VERSION 5.8 ;
BUSBITCHARS "[]" ;
DIVIDERCHAR "/" ;
UNITS
    DATABASE MICRONS 1000 ;
END UNITS

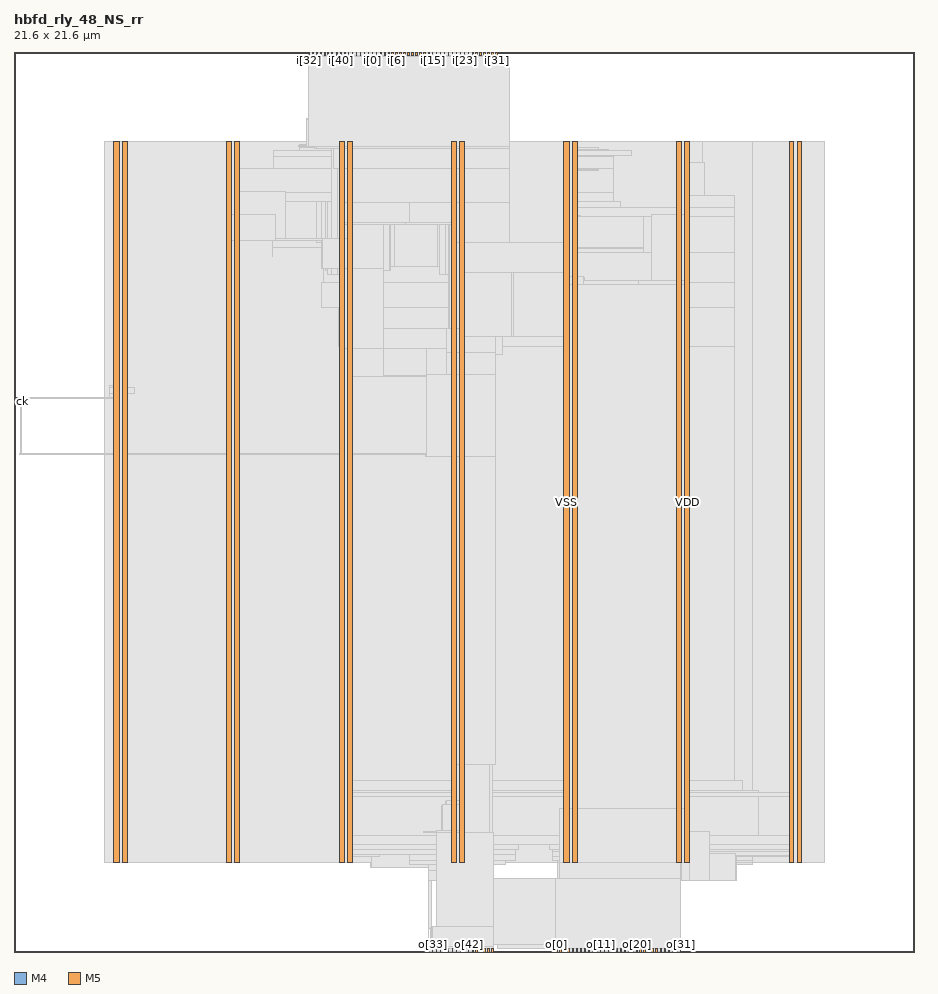
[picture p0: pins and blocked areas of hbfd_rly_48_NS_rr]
MACRO hbfd_rly_48_NS_rr
  FOREIGN hbfd_rly_48_NS_rr 0 0 ;
  CLASS BLOCK ;
  SIZE 21.6 BY 21.6 ;
  PIN ck
    DIRECTION INPUT ;
    USE SIGNAL ;
    PORT
      LAYER M4 ;
        RECT  0 13.2 0.084 13.224 ;
    END
  END ck
  PIN i[0]
    DIRECTION INPUT ;
    USE SIGNAL ;
    PORT
      LAYER M5 ;
        RECT  8.592 21.516 8.616 21.6 ;
    END
  END i[0]
  PIN i[10]
    DIRECTION INPUT ;
    USE SIGNAL ;
    PORT
      LAYER M5 ;
        RECT  9.552 21.516 9.576 21.6 ;
    END
  END i[10]
  PIN i[11]
    DIRECTION INPUT ;
    USE SIGNAL ;
    PORT
      LAYER M5 ;
        RECT  9.648 21.516 9.672 21.6 ;
    END
  END i[11]
  PIN i[12]
    DIRECTION INPUT ;
    USE SIGNAL ;
    PORT
      LAYER M5 ;
        RECT  9.744 21.516 9.768 21.6 ;
    END
  END i[12]
  PIN i[13]
    DIRECTION INPUT ;
    USE SIGNAL ;
    PORT
      LAYER M5 ;
        RECT  9.84 21.516 9.864 21.6 ;
    END
  END i[13]
  PIN i[14]
    DIRECTION INPUT ;
    USE SIGNAL ;
    PORT
      LAYER M5 ;
        RECT  9.936 21.516 9.96 21.6 ;
    END
  END i[14]
  PIN i[15]
    DIRECTION INPUT ;
    USE SIGNAL ;
    PORT
      LAYER M5 ;
        RECT  10.032 21.516 10.056 21.6 ;
    END
  END i[15]
  PIN i[16]
    DIRECTION INPUT ;
    USE SIGNAL ;
    PORT
      LAYER M5 ;
        RECT  10.128 21.516 10.152 21.6 ;
    END
  END i[16]
  PIN i[17]
    DIRECTION INPUT ;
    USE SIGNAL ;
    PORT
      LAYER M5 ;
        RECT  10.224 21.516 10.248 21.6 ;
    END
  END i[17]
  PIN i[18]
    DIRECTION INPUT ;
    USE SIGNAL ;
    PORT
      LAYER M5 ;
        RECT  10.32 21.516 10.344 21.6 ;
    END
  END i[18]
  PIN i[19]
    DIRECTION INPUT ;
    USE SIGNAL ;
    PORT
      LAYER M5 ;
        RECT  10.416 21.516 10.44 21.6 ;
    END
  END i[19]
  PIN i[1]
    DIRECTION INPUT ;
    USE SIGNAL ;
    PORT
      LAYER M5 ;
        RECT  8.688 21.516 8.712 21.6 ;
    END
  END i[1]
  PIN i[20]
    DIRECTION INPUT ;
    USE SIGNAL ;
    PORT
      LAYER M5 ;
        RECT  10.512 21.516 10.536 21.6 ;
    END
  END i[20]
  PIN i[21]
    DIRECTION INPUT ;
    USE SIGNAL ;
    PORT
      LAYER M5 ;
        RECT  10.608 21.516 10.632 21.6 ;
    END
  END i[21]
  PIN i[22]
    DIRECTION INPUT ;
    USE SIGNAL ;
    PORT
      LAYER M5 ;
        RECT  10.704 21.516 10.728 21.6 ;
    END
  END i[22]
  PIN i[23]
    DIRECTION INPUT ;
    USE SIGNAL ;
    PORT
      LAYER M5 ;
        RECT  10.8 21.516 10.824 21.6 ;
    END
  END i[23]
  PIN i[24]
    DIRECTION INPUT ;
    USE SIGNAL ;
    PORT
      LAYER M5 ;
        RECT  10.896 21.516 10.92 21.6 ;
    END
  END i[24]
  PIN i[25]
    DIRECTION INPUT ;
    USE SIGNAL ;
    PORT
      LAYER M5 ;
        RECT  10.992 21.516 11.016 21.6 ;
    END
  END i[25]
  PIN i[26]
    DIRECTION INPUT ;
    USE SIGNAL ;
    PORT
      LAYER M5 ;
        RECT  11.088 21.516 11.112 21.6 ;
    END
  END i[26]
  PIN i[27]
    DIRECTION INPUT ;
    USE SIGNAL ;
    PORT
      LAYER M5 ;
        RECT  11.184 21.516 11.208 21.6 ;
    END
  END i[27]
  PIN i[28]
    DIRECTION INPUT ;
    USE SIGNAL ;
    PORT
      LAYER M5 ;
        RECT  11.28 21.516 11.304 21.6 ;
    END
  END i[28]
  PIN i[29]
    DIRECTION INPUT ;
    USE SIGNAL ;
    PORT
      LAYER M5 ;
        RECT  11.376 21.516 11.4 21.6 ;
    END
  END i[29]
  PIN i[2]
    DIRECTION INPUT ;
    USE SIGNAL ;
    PORT
      LAYER M5 ;
        RECT  8.784 21.516 8.808 21.6 ;
    END
  END i[2]
  PIN i[30]
    DIRECTION INPUT ;
    USE SIGNAL ;
    PORT
      LAYER M5 ;
        RECT  11.472 21.516 11.496 21.6 ;
    END
  END i[30]
  PIN i[31]
    DIRECTION INPUT ;
    USE SIGNAL ;
    PORT
      LAYER M5 ;
        RECT  11.568 21.516 11.592 21.6 ;
    END
  END i[31]
  PIN i[32]
    DIRECTION INPUT ;
    USE SIGNAL ;
    PORT
      LAYER M5 ;
        RECT  7.056 21.516 7.08 21.6 ;
    END
  END i[32]
  PIN i[33]
    DIRECTION INPUT ;
    USE SIGNAL ;
    PORT
      LAYER M5 ;
        RECT  7.152 21.516 7.176 21.6 ;
    END
  END i[33]
  PIN i[34]
    DIRECTION INPUT ;
    USE SIGNAL ;
    PORT
      LAYER M5 ;
        RECT  7.248 21.516 7.272 21.6 ;
    END
  END i[34]
  PIN i[35]
    DIRECTION INPUT ;
    USE SIGNAL ;
    PORT
      LAYER M5 ;
        RECT  7.344 21.516 7.368 21.6 ;
    END
  END i[35]
  PIN i[36]
    DIRECTION INPUT ;
    USE SIGNAL ;
    PORT
      LAYER M5 ;
        RECT  7.44 21.516 7.464 21.6 ;
    END
  END i[36]
  PIN i[37]
    DIRECTION INPUT ;
    USE SIGNAL ;
    PORT
      LAYER M5 ;
        RECT  7.536 21.516 7.56 21.6 ;
    END
  END i[37]
  PIN i[38]
    DIRECTION INPUT ;
    USE SIGNAL ;
    PORT
      LAYER M5 ;
        RECT  7.632 21.516 7.656 21.6 ;
    END
  END i[38]
  PIN i[39]
    DIRECTION INPUT ;
    USE SIGNAL ;
    PORT
      LAYER M5 ;
        RECT  7.728 21.516 7.752 21.6 ;
    END
  END i[39]
  PIN i[3]
    DIRECTION INPUT ;
    USE SIGNAL ;
    PORT
      LAYER M5 ;
        RECT  8.88 21.516 8.904 21.6 ;
    END
  END i[3]
  PIN i[40]
    DIRECTION INPUT ;
    USE SIGNAL ;
    PORT
      LAYER M5 ;
        RECT  7.824 21.516 7.848 21.6 ;
    END
  END i[40]
  PIN i[41]
    DIRECTION INPUT ;
    USE SIGNAL ;
    PORT
      LAYER M5 ;
        RECT  7.92 21.516 7.944 21.6 ;
    END
  END i[41]
  PIN i[42]
    DIRECTION INPUT ;
    USE SIGNAL ;
    PORT
      LAYER M5 ;
        RECT  8.016 21.516 8.04 21.6 ;
    END
  END i[42]
  PIN i[43]
    DIRECTION INPUT ;
    USE SIGNAL ;
    PORT
      LAYER M5 ;
        RECT  8.112 21.516 8.136 21.6 ;
    END
  END i[43]
  PIN i[44]
    DIRECTION INPUT ;
    USE SIGNAL ;
    PORT
      LAYER M5 ;
        RECT  8.208 21.516 8.232 21.6 ;
    END
  END i[44]
  PIN i[45]
    DIRECTION INPUT ;
    USE SIGNAL ;
    PORT
      LAYER M5 ;
        RECT  8.304 21.516 8.328 21.6 ;
    END
  END i[45]
  PIN i[46]
    DIRECTION INPUT ;
    USE SIGNAL ;
    PORT
      LAYER M5 ;
        RECT  8.4 21.516 8.424 21.6 ;
    END
  END i[46]
  PIN i[47]
    DIRECTION INPUT ;
    USE SIGNAL ;
    PORT
      LAYER M5 ;
        RECT  8.496 21.516 8.52 21.6 ;
    END
  END i[47]
  PIN i[4]
    DIRECTION INPUT ;
    USE SIGNAL ;
    PORT
      LAYER M5 ;
        RECT  8.976 21.516 9 21.6 ;
    END
  END i[4]
  PIN i[5]
    DIRECTION INPUT ;
    USE SIGNAL ;
    PORT
      LAYER M5 ;
        RECT  9.072 21.516 9.096 21.6 ;
    END
  END i[5]
  PIN i[6]
    DIRECTION INPUT ;
    USE SIGNAL ;
    PORT
      LAYER M5 ;
        RECT  9.168 21.516 9.192 21.6 ;
    END
  END i[6]
  PIN i[7]
    DIRECTION INPUT ;
    USE SIGNAL ;
    PORT
      LAYER M5 ;
        RECT  9.264 21.516 9.288 21.6 ;
    END
  END i[7]
  PIN i[8]
    DIRECTION INPUT ;
    USE SIGNAL ;
    PORT
      LAYER M5 ;
        RECT  9.36 21.516 9.384 21.6 ;
    END
  END i[8]
  PIN i[9]
    DIRECTION INPUT ;
    USE SIGNAL ;
    PORT
      LAYER M5 ;
        RECT  9.456 21.516 9.48 21.6 ;
    END
  END i[9]
  PIN o[0]
    DIRECTION OUTPUT ;
    USE SIGNAL ;
    PORT
      LAYER M5 ;
        RECT  13.008 0 13.032 0.084 ;
    END
  END o[0]
  PIN o[10]
    DIRECTION OUTPUT ;
    USE SIGNAL ;
    PORT
      LAYER M5 ;
        RECT  13.968 0 13.992 0.084 ;
    END
  END o[10]
  PIN o[11]
    DIRECTION OUTPUT ;
    USE SIGNAL ;
    PORT
      LAYER M5 ;
        RECT  14.064 0 14.088 0.084 ;
    END
  END o[11]
  PIN o[12]
    DIRECTION OUTPUT ;
    USE SIGNAL ;
    PORT
      LAYER M5 ;
        RECT  14.16 0 14.184 0.084 ;
    END
  END o[12]
  PIN o[13]
    DIRECTION OUTPUT ;
    USE SIGNAL ;
    PORT
      LAYER M5 ;
        RECT  14.256 0 14.28 0.084 ;
    END
  END o[13]
  PIN o[14]
    DIRECTION OUTPUT ;
    USE SIGNAL ;
    PORT
      LAYER M5 ;
        RECT  14.352 0 14.376 0.084 ;
    END
  END o[14]
  PIN o[15]
    DIRECTION OUTPUT ;
    USE SIGNAL ;
    PORT
      LAYER M5 ;
        RECT  14.448 0 14.472 0.084 ;
    END
  END o[15]
  PIN o[16]
    DIRECTION OUTPUT ;
    USE SIGNAL ;
    PORT
      LAYER M5 ;
        RECT  14.544 0 14.568 0.084 ;
    END
  END o[16]
  PIN o[17]
    DIRECTION OUTPUT ;
    USE SIGNAL ;
    PORT
      LAYER M5 ;
        RECT  14.64 0 14.664 0.084 ;
    END
  END o[17]
  PIN o[18]
    DIRECTION OUTPUT ;
    USE SIGNAL ;
    PORT
      LAYER M5 ;
        RECT  14.736 0 14.76 0.084 ;
    END
  END o[18]
  PIN o[19]
    DIRECTION OUTPUT ;
    USE SIGNAL ;
    PORT
      LAYER M5 ;
        RECT  14.832 0 14.856 0.084 ;
    END
  END o[19]
  PIN o[1]
    DIRECTION OUTPUT ;
    USE SIGNAL ;
    PORT
      LAYER M5 ;
        RECT  13.104 0 13.128 0.084 ;
    END
  END o[1]
  PIN o[20]
    DIRECTION OUTPUT ;
    USE SIGNAL ;
    PORT
      LAYER M5 ;
        RECT  14.928 0 14.952 0.084 ;
    END
  END o[20]
  PIN o[21]
    DIRECTION OUTPUT ;
    USE SIGNAL ;
    PORT
      LAYER M5 ;
        RECT  15.024 0 15.048 0.084 ;
    END
  END o[21]
  PIN o[22]
    DIRECTION OUTPUT ;
    USE SIGNAL ;
    PORT
      LAYER M5 ;
        RECT  15.12 0 15.144 0.084 ;
    END
  END o[22]
  PIN o[23]
    DIRECTION OUTPUT ;
    USE SIGNAL ;
    PORT
      LAYER M5 ;
        RECT  15.216 0 15.24 0.084 ;
    END
  END o[23]
  PIN o[24]
    DIRECTION OUTPUT ;
    USE SIGNAL ;
    PORT
      LAYER M5 ;
        RECT  15.312 0 15.336 0.084 ;
    END
  END o[24]
  PIN o[25]
    DIRECTION OUTPUT ;
    USE SIGNAL ;
    PORT
      LAYER M5 ;
        RECT  15.408 0 15.432 0.084 ;
    END
  END o[25]
  PIN o[26]
    DIRECTION OUTPUT ;
    USE SIGNAL ;
    PORT
      LAYER M5 ;
        RECT  15.504 0 15.528 0.084 ;
    END
  END o[26]
  PIN o[27]
    DIRECTION OUTPUT ;
    USE SIGNAL ;
    PORT
      LAYER M5 ;
        RECT  15.6 0 15.624 0.084 ;
    END
  END o[27]
  PIN o[28]
    DIRECTION OUTPUT ;
    USE SIGNAL ;
    PORT
      LAYER M5 ;
        RECT  15.696 0 15.72 0.084 ;
    END
  END o[28]
  PIN o[29]
    DIRECTION OUTPUT ;
    USE SIGNAL ;
    PORT
      LAYER M5 ;
        RECT  15.792 0 15.816 0.084 ;
    END
  END o[29]
  PIN o[2]
    DIRECTION OUTPUT ;
    USE SIGNAL ;
    PORT
      LAYER M5 ;
        RECT  13.2 0 13.224 0.084 ;
    END
  END o[2]
  PIN o[30]
    DIRECTION OUTPUT ;
    USE SIGNAL ;
    PORT
      LAYER M5 ;
        RECT  15.888 0 15.912 0.084 ;
    END
  END o[30]
  PIN o[31]
    DIRECTION OUTPUT ;
    USE SIGNAL ;
    PORT
      LAYER M5 ;
        RECT  15.984 0 16.008 0.084 ;
    END
  END o[31]
  PIN o[32]
    DIRECTION OUTPUT ;
    USE SIGNAL ;
    PORT
      LAYER M5 ;
        RECT  9.936 0 9.96 0.084 ;
    END
  END o[32]
  PIN o[33]
    DIRECTION OUTPUT ;
    USE SIGNAL ;
    PORT
      LAYER M5 ;
        RECT  10.032 0 10.056 0.084 ;
    END
  END o[33]
  PIN o[34]
    DIRECTION OUTPUT ;
    USE SIGNAL ;
    PORT
      LAYER M5 ;
        RECT  10.128 0 10.152 0.084 ;
    END
  END o[34]
  PIN o[35]
    DIRECTION OUTPUT ;
    USE SIGNAL ;
    PORT
      LAYER M5 ;
        RECT  10.224 0 10.248 0.084 ;
    END
  END o[35]
  PIN o[36]
    DIRECTION OUTPUT ;
    USE SIGNAL ;
    PORT
      LAYER M5 ;
        RECT  10.32 0 10.344 0.084 ;
    END
  END o[36]
  PIN o[37]
    DIRECTION OUTPUT ;
    USE SIGNAL ;
    PORT
      LAYER M5 ;
        RECT  10.416 0 10.44 0.084 ;
    END
  END o[37]
  PIN o[38]
    DIRECTION OUTPUT ;
    USE SIGNAL ;
    PORT
      LAYER M5 ;
        RECT  10.512 0 10.536 0.084 ;
    END
  END o[38]
  PIN o[39]
    DIRECTION OUTPUT ;
    USE SIGNAL ;
    PORT
      LAYER M5 ;
        RECT  10.608 0 10.632 0.084 ;
    END
  END o[39]
  PIN o[3]
    DIRECTION OUTPUT ;
    USE SIGNAL ;
    PORT
      LAYER M5 ;
        RECT  13.296 0 13.32 0.084 ;
    END
  END o[3]
  PIN o[40]
    DIRECTION OUTPUT ;
    USE SIGNAL ;
    PORT
      LAYER M5 ;
        RECT  10.704 0 10.728 0.084 ;
    END
  END o[40]
  PIN o[41]
    DIRECTION OUTPUT ;
    USE SIGNAL ;
    PORT
      LAYER M5 ;
        RECT  10.8 0 10.824 0.084 ;
    END
  END o[41]
  PIN o[42]
    DIRECTION OUTPUT ;
    USE SIGNAL ;
    PORT
      LAYER M5 ;
        RECT  10.896 0 10.92 0.084 ;
    END
  END o[42]
  PIN o[43]
    DIRECTION OUTPUT ;
    USE SIGNAL ;
    PORT
      LAYER M5 ;
        RECT  10.992 0 11.016 0.084 ;
    END
  END o[43]
  PIN o[44]
    DIRECTION OUTPUT ;
    USE SIGNAL ;
    PORT
      LAYER M5 ;
        RECT  11.088 0 11.112 0.084 ;
    END
  END o[44]
  PIN o[45]
    DIRECTION OUTPUT ;
    USE SIGNAL ;
    PORT
      LAYER M5 ;
        RECT  11.184 0 11.208 0.084 ;
    END
  END o[45]
  PIN o[46]
    DIRECTION OUTPUT ;
    USE SIGNAL ;
    PORT
      LAYER M5 ;
        RECT  11.28 0 11.304 0.084 ;
    END
  END o[46]
  PIN o[47]
    DIRECTION OUTPUT ;
    USE SIGNAL ;
    PORT
      LAYER M5 ;
        RECT  11.376 0 11.4 0.084 ;
    END
  END o[47]
  PIN o[4]
    DIRECTION OUTPUT ;
    USE SIGNAL ;
    PORT
      LAYER M5 ;
        RECT  13.392 0 13.416 0.084 ;
    END
  END o[4]
  PIN o[5]
    DIRECTION OUTPUT ;
    USE SIGNAL ;
    PORT
      LAYER M5 ;
        RECT  13.488 0 13.512 0.084 ;
    END
  END o[5]
  PIN o[6]
    DIRECTION OUTPUT ;
    USE SIGNAL ;
    PORT
      LAYER M5 ;
        RECT  13.584 0 13.608 0.084 ;
    END
  END o[6]
  PIN o[7]
    DIRECTION OUTPUT ;
    USE SIGNAL ;
    PORT
      LAYER M5 ;
        RECT  13.68 0 13.704 0.084 ;
    END
  END o[7]
  PIN o[8]
    DIRECTION OUTPUT ;
    USE SIGNAL ;
    PORT
      LAYER M5 ;
        RECT  13.776 0 13.8 0.084 ;
    END
  END o[8]
  PIN o[9]
    DIRECTION OUTPUT ;
    USE SIGNAL ;
    PORT
      LAYER M5 ;
        RECT  13.872 0 13.896 0.084 ;
    END
  END o[9]
  PIN rs
    DIRECTION INPUT ;
    USE SIGNAL ;
    PORT
      LAYER M4 ;
        RECT  0 13.296 0.084 13.32 ;
    END
  END rs
  PIN rso
    DIRECTION OUTPUT ;
    USE SIGNAL ;
    PORT
      LAYER M5 ;
        RECT  11.472 0 11.496 0.084 ;
    END
  END rso
  PIN VDD
    DIRECTION INOUT ;
    USE POWER ;
    PORT
      LAYER M5 ;
        RECT  18.792 2.151 18.912 19.449 ;
        RECT  16.092 2.151 16.212 19.449 ;
        RECT  13.392 2.151 13.512 19.449 ;
        RECT  10.692 2.151 10.812 19.449 ;
        RECT  7.992 2.151 8.112 19.449 ;
        RECT  5.292 2.151 5.412 19.449 ;
        RECT  2.592 2.151 2.712 19.449 ;
    END
  END VDD
  PIN VSS
    DIRECTION INOUT ;
    USE GROUND ;
    PORT
      LAYER M5 ;
        RECT  18.6 2.137 18.72 19.463 ;
        RECT  15.9 2.137 16.02 19.463 ;
        RECT  13.2 2.137 13.32 19.463 ;
        RECT  10.5 2.137 10.62 19.463 ;
        RECT  7.8 2.137 7.92 19.463 ;
        RECT  5.1 2.137 5.22 19.463 ;
        RECT  2.4 2.137 2.52 19.463 ;
    END
  END VSS
  # OT_OBS_CLOSED layer=M5 d_um=1.536 added=14
  OBS
    LAYER RVTN ;
     RECT  2.16 2.16 19.44 2.295 ;
     RECT  2.16 2.565 19.44 2.835 ;
     RECT  2.16 3.105 19.44 3.375 ;
     RECT  2.16 3.645 19.44 3.915 ;
     RECT  2.16 4.185 19.44 4.455 ;
     RECT  2.16 4.725 19.44 4.995 ;
     RECT  2.16 5.265 19.44 5.535 ;
     RECT  2.16 5.805 19.44 6.075 ;
     RECT  2.16 6.345 19.44 6.615 ;
     RECT  2.16 6.885 19.44 7.155 ;
     RECT  2.16 7.425 19.44 7.695 ;
     RECT  2.16 7.965 19.44 8.235 ;
     RECT  2.16 8.505 19.44 8.775 ;
     RECT  2.16 9.045 19.44 9.315 ;
     RECT  2.16 9.585 19.44 9.855 ;
     RECT  2.16 10.125 19.44 10.395 ;
     RECT  2.16 10.665 19.44 10.935 ;
     RECT  2.16 11.205 19.44 11.475 ;
     RECT  2.16 11.745 19.44 12.015 ;
     RECT  2.16 12.285 19.44 12.555 ;
     RECT  2.16 12.825 19.44 13.095 ;
     RECT  2.16 13.365 19.44 13.635 ;
     RECT  2.16 13.905 19.44 14.175 ;
     RECT  2.16 14.445 19.44 14.715 ;
     RECT  2.16 14.985 19.44 15.255 ;
     RECT  2.16 15.525 19.44 15.795 ;
     RECT  2.16 16.065 19.44 16.335 ;
     RECT  2.16 16.605 19.44 16.875 ;
     RECT  2.16 17.145 19.44 17.415 ;
     RECT  2.16 17.685 19.44 17.955 ;
     RECT  2.16 18.225 19.44 18.495 ;
     RECT  2.16 18.765 19.44 19.035 ;
     RECT  2.16 19.305 19.44 19.44 ;
    LAYER RVTP ;
     RECT  2.16 2.295 19.44 2.565 ;
     RECT  2.16 2.835 19.44 3.105 ;
     RECT  2.16 3.375 19.44 3.645 ;
     RECT  2.16 3.915 19.44 4.185 ;
     RECT  2.16 4.455 19.44 4.725 ;
     RECT  2.16 4.995 19.44 5.265 ;
     RECT  2.16 5.535 19.44 5.805 ;
     RECT  2.16 6.075 19.44 6.345 ;
     RECT  2.16 6.615 19.44 6.885 ;
     RECT  2.16 7.155 19.44 7.425 ;
     RECT  2.16 7.695 19.44 7.965 ;
     RECT  2.16 8.235 19.44 8.505 ;
     RECT  2.16 8.775 19.44 9.045 ;
     RECT  2.16 9.315 19.44 9.585 ;
     RECT  2.16 9.855 19.44 10.125 ;
     RECT  2.16 10.395 19.44 10.665 ;
     RECT  2.16 10.935 19.44 11.205 ;
     RECT  2.16 11.475 19.44 11.745 ;
     RECT  2.16 12.015 19.44 12.285 ;
     RECT  2.16 12.555 19.44 12.825 ;
     RECT  2.16 13.095 19.44 13.365 ;
     RECT  2.16 13.635 19.44 13.905 ;
     RECT  2.16 14.175 19.44 14.445 ;
     RECT  2.16 14.715 19.44 14.985 ;
     RECT  2.16 15.255 19.44 15.525 ;
     RECT  2.16 15.795 19.44 16.065 ;
     RECT  2.16 16.335 19.44 16.605 ;
     RECT  2.16 16.875 19.44 17.145 ;
     RECT  2.16 17.415 19.44 17.685 ;
     RECT  2.16 17.955 19.44 18.225 ;
     RECT  2.16 18.495 19.44 18.765 ;
     RECT  2.16 19.035 19.44 19.305 ;
    LAYER M1 ;
     RECT  2.16 2.151 19.44 19.449 ;
    LAYER M2 ;
     RECT  2.16 2.151 8.563 19.449 ;
     RECT  8.563 2.034 10.355 19.449 ;
     RECT  10.355 2.07 11.363 19.449 ;
     RECT  11.363 2.106 11.795 19.449 ;
     RECT  14.251 1.152 14.495 1.17 ;
     RECT  11.795 2.151 16.519 19.449 ;
     RECT  16.519 2.106 17.735 19.449 ;
     RECT  17.735 2.151 19.44 19.449 ;
    LAYER M3 ;
     RECT  13.608 0.091 14.382 0.523 ;
     RECT  9.936 0.091 9.954 0.571 ;
     RECT  13.356 0.523 14.382 1.099 ;
     RECT  13.14 1.099 14.922 1.195 ;
     RECT  9.936 0.571 10.026 1.723 ;
     RECT  11.124 0.091 11.142 1.723 ;
     RECT  13.104 1.195 14.922 1.723 ;
     RECT  16.524 1.771 16.542 1.819 ;
     RECT  17.316 1.723 17.334 1.819 ;
     RECT  16.524 1.819 17.334 1.915 ;
     RECT  9.936 1.723 10.386 1.963 ;
     RECT  11.124 1.723 11.394 1.963 ;
     RECT  9.936 1.963 11.394 2.101 ;
     RECT  16.308 1.915 17.334 2.101 ;
     RECT  8.568 2.029 8.586 2.143 ;
     RECT  13.032 1.723 15.246 2.143 ;
     RECT  16.308 2.101 17.73 2.143 ;
     RECT  9.504 2.101 11.79 2.191 ;
     RECT  13.032 2.143 17.73 2.191 ;
     RECT  7.815 2.143 8.586 2.299 ;
     RECT  12.924 2.191 17.73 2.299 ;
     RECT  18.615 2.143 18.705 2.299 ;
     RECT  7.815 2.299 8.766 2.335 ;
     RECT  9.504 2.191 12.042 2.335 ;
     RECT  2.415 2.143 2.505 2.413 ;
     RECT  5.115 2.143 5.205 2.413 ;
     RECT  12.924 2.299 18.705 2.413 ;
     RECT  7.815 2.335 12.042 2.461 ;
     RECT  12.924 2.413 18.897 2.461 ;
     RECT  7.815 2.461 12.114 2.569 ;
     RECT  12.852 2.461 18.897 2.569 ;
     RECT  7.815 2.569 18.897 2.795 ;
     RECT  7.815 2.795 17.874 3.721 ;
     RECT  18.615 2.795 18.897 3.721 ;
     RECT  7.815 3.721 18.897 3.839 ;
     RECT  7.815 3.839 17.874 3.875 ;
     RECT  7.815 3.875 17.478 4.109 ;
     RECT  2.415 2.413 2.697 13.291 ;
     RECT  2.304 13.291 2.697 13.405 ;
     RECT  2.304 13.405 2.898 13.559 ;
     RECT  2.304 13.559 2.697 13.595 ;
     RECT  7.815 4.109 17.298 14.521 ;
     RECT  7.776 14.521 17.298 15.457 ;
     RECT  7.38 15.457 17.298 16.061 ;
     RECT  7.416 16.061 17.298 16.799 ;
     RECT  7.416 16.799 15.102 16.879 ;
     RECT  6.192 16.681 6.21 16.915 ;
     RECT  7.38 16.879 15.102 16.915 ;
     RECT  6.192 16.915 15.102 17.659 ;
     RECT  15.915 16.799 17.298 17.659 ;
     RECT  6.156 17.659 17.298 17.879 ;
     RECT  6.156 17.879 14.562 18.023 ;
     RECT  15.915 17.879 17.298 18.149 ;
     RECT  5.115 2.413 5.397 18.235 ;
     RECT  6.156 18.023 14.382 18.235 ;
     RECT  5.115 18.235 14.382 18.797 ;
     RECT  15.915 18.149 16.578 18.959 ;
     RECT  6.228 18.797 14.382 19.103 ;
     RECT  13.212 19.103 14.382 19.111 ;
     RECT  2.415 13.595 2.697 19.187 ;
     RECT  5.115 18.797 5.397 19.187 ;
     RECT  15.915 18.959 16.197 19.187 ;
     RECT  18.615 3.839 18.897 19.187 ;
     RECT  6.228 19.103 12.474 19.229 ;
     RECT  13.212 19.111 14.814 19.229 ;
     RECT  13.212 19.229 14.274 19.265 ;
     RECT  6.84 19.229 12.33 19.301 ;
     RECT  13.212 19.265 14.022 19.301 ;
     RECT  6.84 19.301 12.042 19.325 ;
     RECT  9.648 19.325 12.042 19.337 ;
     RECT  6.84 19.325 8.91 19.373 ;
     RECT  9.648 19.337 11.214 19.373 ;
     RECT  12.024 19.337 12.042 19.373 ;
     RECT  13.212 19.301 13.305 19.373 ;
     RECT  6.84 19.373 8.118 19.379 ;
     RECT  2.415 19.187 2.505 19.457 ;
     RECT  5.115 19.187 5.205 19.457 ;
     RECT  13.215 19.373 13.305 19.457 ;
     RECT  15.915 19.187 16.005 19.457 ;
     RECT  18.615 19.187 18.705 19.457 ;
     RECT  10.404 19.373 11.034 19.565 ;
     RECT  7.02 19.379 8.118 19.613 ;
     RECT  10.476 19.565 11.034 19.613 ;
     RECT  7.02 19.613 7.794 19.661 ;
     RECT  7.02 19.661 7.65 19.997 ;
     RECT  7.38 19.997 7.65 20.045 ;
     RECT  7.632 20.045 7.65 20.573 ;
     RECT  11.016 19.613 11.034 21.485 ;
    LAYER M4 ;
     RECT  0.084 13.2 0.179 13.224 ;
     RECT  0.06 13.224 0.179 13.296 ;
     RECT  0.084 13.296 0.179 13.32 ;
     RECT  0.133 11.952 2.408 11.976 ;
     RECT  0.179 13.296 2.408 13.32 ;
     RECT  2.408 2.148 2.512 19.452 ;
     RECT  2.512 2.418 2.704 19.182 ;
     RECT  2.704 11.952 5.108 11.976 ;
     RECT  5.108 2.148 5.212 19.452 ;
     RECT  5.212 2.418 5.404 19.182 ;
     RECT  5.404 17.088 6.509 18.264 ;
     RECT  6.829 19.344 7.009 19.368 ;
     RECT  7.009 19.344 7.217 19.992 ;
     RECT  6.509 17.088 7.261 18.024 ;
     RECT  7.261 17.04 7.369 18.024 ;
     RECT  7.217 19.296 7.369 19.992 ;
     RECT  7.369 16.896 7.381 18.024 ;
     RECT  7.381 16.416 7.477 18.024 ;
     RECT  7.477 16.368 7.513 18.024 ;
     RECT  7.369 19.296 7.621 20.04 ;
     RECT  7.513 16.272 7.628 18.024 ;
     RECT  7.621 19.296 7.628 20.568 ;
     RECT  7.628 16.272 7.763 20.568 ;
     RECT  5.404 11.952 7.808 11.976 ;
     RECT  7.763 16.272 7.808 19.656 ;
     RECT  7.808 2.148 7.912 19.656 ;
     RECT  7.912 2.418 7.955 19.656 ;
     RECT  7.955 2.418 8.104 19.608 ;
     RECT  8.104 16.272 8.173 19.608 ;
     RECT  8.173 16.272 8.525 19.416 ;
     RECT  8.525 16.32 8.633 19.416 ;
     RECT  8.104 13.824 8.867 14.52 ;
     RECT  8.917 21.408 8.965 21.432 ;
     RECT  8.633 16.368 9.011 19.416 ;
     RECT  9.011 16.368 9.029 19.368 ;
     RECT  8.965 21.216 9.107 21.432 ;
     RECT  9.029 16.464 9.137 19.368 ;
     RECT  8.104 11.952 9.877 11.976 ;
     RECT  9.925 0.096 9.997 0.12 ;
     RECT  9.997 0.096 10.009 0.6 ;
     RECT  10.009 0.144 10.081 0.6 ;
     RECT  9.137 16.464 10.172 17.544 ;
     RECT  9.137 18.768 10.172 19.368 ;
     RECT  10.172 16.464 10.213 19.368 ;
     RECT  9.817 2.88 10.261 2.904 ;
     RECT  10.177 1.776 10.285 1.8 ;
     RECT  10.261 2.88 10.285 3.528 ;
     RECT  10.285 1.776 10.357 3.528 ;
     RECT  10.213 16.272 10.364 19.368 ;
     RECT  10.357 14.928 10.429 14.952 ;
     RECT  10.364 16.272 10.429 19.56 ;
     RECT  10.429 14.928 10.45 19.56 ;
     RECT  10.357 1.728 10.508 3.624 ;
     RECT  9.877 11.904 10.508 11.976 ;
     RECT  8.867 13.824 10.508 13.848 ;
     RECT  10.45 14.928 10.508 19.608 ;
     RECT  10.357 21.408 10.547 21.432 ;
     RECT  10.081 0.144 10.643 0.216 ;
     RECT  10.508 1.728 10.804 19.608 ;
     RECT  10.804 14.352 10.829 19.608 ;
     RECT  10.829 18.816 10.835 19.608 ;
     RECT  11.069 0.096 11.153 0.12 ;
     RECT  10.835 18.816 11.225 19.368 ;
     RECT  11.225 18.816 11.333 19.32 ;
     RECT  10.804 1.728 11.405 4.536 ;
     RECT  11.333 18.816 11.405 19.272 ;
     RECT  11.405 2.256 11.411 4.536 ;
     RECT  11.411 2.832 11.477 4.536 ;
     RECT  11.477 2.832 11.507 2.856 ;
     RECT  11.477 4.512 11.555 4.536 ;
     RECT  10.829 14.352 11.729 17.112 ;
     RECT  10.597 21.456 11.891 21.48 ;
     RECT  11.729 14.784 11.987 17.112 ;
     RECT  11.987 15.456 12.089 17.112 ;
     RECT  12.089 15.936 12.193 17.112 ;
     RECT  11.405 18.816 12.193 18.84 ;
     RECT  12.193 18.72 12.233 18.84 ;
     RECT  12.233 18.72 12.625 18.744 ;
     RECT  12.193 15.936 13.057 17.688 ;
     RECT  12.625 18.672 13.057 18.744 ;
     RECT  12.977 1.728 13.093 1.752 ;
     RECT  13.093 1.2 13.129 1.752 ;
     RECT  13.129 1.104 13.208 1.752 ;
     RECT  13.093 3.408 13.208 3.432 ;
     RECT  13.057 15.936 13.208 18.744 ;
     RECT  13.208 1.104 13.312 19.452 ;
     RECT  13.312 1.104 13.331 1.224 ;
     RECT  13.312 2.256 13.504 19.182 ;
     RECT  13.34 0.528 13.553 0.648 ;
     RECT  13.504 17.664 13.601 17.688 ;
     RECT  13.504 2.256 13.619 5.16 ;
     RECT  13.504 15.984 13.681 16.2 ;
     RECT  13.553 0.096 13.9 0.648 ;
     RECT  13.504 14.928 13.907 15 ;
     RECT  13.504 18.768 14.033 18.792 ;
     RECT  13.9 0.096 14.329 0.552 ;
     RECT  13.681 15.984 14.329 16.008 ;
     RECT  14.329 0.096 14.393 0.12 ;
     RECT  13.619 3.984 14.501 5.16 ;
     RECT  13.907 14.976 14.531 15 ;
     RECT  13.504 6.24 14.677 6.264 ;
     RECT  14.677 5.664 14.915 6.264 ;
     RECT  13.619 2.256 14.917 2.904 ;
     RECT  14.501 3.984 14.917 4.584 ;
     RECT  14.876 1.104 14.963 1.128 ;
     RECT  14.917 2.256 14.993 4.584 ;
     RECT  14.677 16.08 15.505 16.104 ;
     RECT  14.993 1.728 15.908 4.584 ;
     RECT  14.915 5.664 15.908 5.688 ;
     RECT  15.505 16.08 15.908 16.584 ;
     RECT  15.301 17.664 15.908 17.688 ;
     RECT  15.733 0.144 15.923 0.168 ;
     RECT  15.908 1.728 16.012 19.452 ;
     RECT  16.012 1.728 16.204 19.182 ;
     RECT  16.204 1.728 16.697 2.904 ;
     RECT  16.697 1.728 17.309 2.376 ;
     RECT  17.309 1.728 17.345 2.328 ;
     RECT  17.345 2.304 18.608 2.328 ;
     RECT  18.608 2.148 18.712 19.452 ;
     RECT  18.712 2.418 18.904 19.182 ;
    LAYER M5 ;
     RECT  9.96 0.016 10.032 0.084 ;
     RECT  10.056 0.016 10.128 0.084 ;
     RECT  10.152 0.016 10.224 0.084 ;
     RECT  10.248 0.016 10.32 0.084 ;
     RECT  10.344 0.016 10.416 0.084 ;
     RECT  10.44 0.016 10.512 0.084 ;
     RECT  10.536 0.016 10.608 0.084 ;
     RECT  10.632 0.016 10.704 0.084 ;
     RECT  10.728 0.016 10.8 0.084 ;
     RECT  10.824 0.016 10.896 0.084 ;
     RECT  10.92 0.016 10.992 0.084 ;
     RECT  11.016 0.016 11.088 0.084 ;
     RECT  11.112 0.016 11.184 0.084 ;
     RECT  11.208 0.016 11.28 0.084 ;
     RECT  11.304 0.016 11.376 0.084 ;
     RECT  11.4 0.016 11.472 0.084 ;
     RECT  9.936 0.084 11.496 0.131 ;
     RECT  10.032 0.131 11.496 0.611 ;
     RECT  13.032 0.016 13.104 0.084 ;
     RECT  13.128 0.016 13.2 0.084 ;
     RECT  13.224 0.016 13.296 0.084 ;
     RECT  13.32 0.016 13.392 0.084 ;
     RECT  13.416 0.016 13.488 0.084 ;
     RECT  13.512 0.016 13.584 0.084 ;
     RECT  13.608 0.016 13.68 0.084 ;
     RECT  13.704 0.016 13.776 0.084 ;
     RECT  13.8 0.016 13.872 0.084 ;
     RECT  13.896 0.016 13.968 0.084 ;
     RECT  13.992 0.016 14.064 0.084 ;
     RECT  14.088 0.016 14.16 0.084 ;
     RECT  14.184 0.016 14.256 0.084 ;
     RECT  14.28 0.016 14.352 0.084 ;
     RECT  14.376 0.016 14.448 0.084 ;
     RECT  14.472 0.016 14.544 0.084 ;
     RECT  14.568 0.016 14.64 0.084 ;
     RECT  14.664 0.016 14.736 0.084 ;
     RECT  14.76 0.016 14.832 0.084 ;
     RECT  14.856 0.016 14.928 0.084 ;
     RECT  14.952 0.016 15.024 0.084 ;
     RECT  15.048 0.016 15.12 0.084 ;
     RECT  15.144 0.016 15.216 0.084 ;
     RECT  15.24 0.016 15.312 0.084 ;
     RECT  15.336 0.016 15.408 0.084 ;
     RECT  15.432 0.016 15.504 0.084 ;
     RECT  15.528 0.016 15.6 0.084 ;
     RECT  15.624 0.016 15.696 0.084 ;
     RECT  15.72 0.016 15.792 0.084 ;
     RECT  15.816 0.016 15.888 0.084 ;
     RECT  15.912 0.016 15.984 0.084 ;
     RECT  13.008 0.084 16.008 1.763 ;
     RECT  13.104 1.763 16.008 2.137 ;
     RECT  2.4 2.137 2.52 2.151 ;
     RECT  5.1 2.137 5.22 2.151 ;
     RECT  7.8 2.137 7.92 2.151 ;
     RECT  13.104 2.137 16.02 2.151 ;
     RECT  18.6 2.137 18.72 2.151 ;
     RECT  10.128 0.611 11.496 2.867 ;
     RECT  10.128 2.867 10.812 2.915 ;
     RECT  13.104 2.151 16.212 3.443 ;
     RECT  10.272 2.915 10.812 3.539 ;
     RECT  10.368 3.539 10.812 3.635 ;
     RECT  10.5 3.635 10.812 4.501 ;
     RECT  10.5 4.501 11.544 11.893 ;
     RECT  0.144 11.941 0.168 13.235 ;
     RECT  9.888 11.893 11.544 13.859 ;
     RECT  10.368 13.859 11.544 14.387 ;
     RECT  7.8 2.151 8.112 14.485 ;
     RECT  10.368 14.387 10.812 14.963 ;
     RECT  13.2 3.443 16.212 16.019 ;
     RECT  14.976 16.019 16.212 16.115 ;
     RECT  13.2 16.019 13.656 16.211 ;
     RECT  11.952 14.773 11.976 16.307 ;
     RECT  7.8 14.485 8.856 16.403 ;
     RECT  7.8 16.403 8.112 16.405 ;
     RECT  10.5 14.963 10.812 17.029 ;
     RECT  5.1 2.151 5.412 17.077 ;
     RECT  7.392 16.405 8.112 17.123 ;
     RECT  7.8 17.123 8.112 17.461 ;
     RECT  7.8 17.461 9.384 17.509 ;
     RECT  5.1 17.077 6.264 17.699 ;
     RECT  15.312 16.115 16.212 17.699 ;
     RECT  7.8 17.509 9.48 17.989 ;
     RECT  10.5 17.029 11.88 17.989 ;
     RECT  7.8 17.989 11.88 18.805 ;
     RECT  7.68 18.805 11.88 19.285 ;
     RECT  7.248 19.285 11.88 19.333 ;
     RECT  2.4 2.151 2.712 19.449 ;
     RECT  5.1 17.699 5.412 19.449 ;
     RECT  13.2 16.211 13.512 19.449 ;
     RECT  15.9 17.699 16.212 19.449 ;
     RECT  18.6 2.151 18.912 19.449 ;
     RECT  2.4 19.449 2.52 19.463 ;
     RECT  5.1 19.449 5.22 19.463 ;
     RECT  13.2 19.449 13.32 19.463 ;
     RECT  15.9 19.449 16.02 19.463 ;
     RECT  18.6 19.449 18.72 19.463 ;
     RECT  7.056 19.333 11.88 21.491 ;
     RECT  7.056 21.491 11.592 21.516 ;
     RECT  7.08 21.516 7.152 21.584 ;
     RECT  7.176 21.516 7.248 21.584 ;
     RECT  7.272 21.516 7.344 21.584 ;
     RECT  7.368 21.516 7.44 21.584 ;
     RECT  7.464 21.516 7.536 21.584 ;
     RECT  7.56 21.516 7.632 21.584 ;
     RECT  7.656 21.516 7.728 21.584 ;
     RECT  7.752 21.516 7.824 21.584 ;
     RECT  7.848 21.516 7.92 21.584 ;
     RECT  7.944 21.516 8.016 21.584 ;
     RECT  8.04 21.516 8.112 21.584 ;
     RECT  8.136 21.516 8.208 21.584 ;
     RECT  8.232 21.516 8.304 21.584 ;
     RECT  8.328 21.516 8.4 21.584 ;
     RECT  8.424 21.516 8.496 21.584 ;
     RECT  8.52 21.516 8.592 21.584 ;
     RECT  8.616 21.516 8.688 21.584 ;
     RECT  8.712 21.516 8.784 21.584 ;
     RECT  8.808 21.516 8.88 21.584 ;
     RECT  8.904 21.516 8.976 21.584 ;
     RECT  9 21.516 9.072 21.584 ;
     RECT  9.096 21.516 9.168 21.584 ;
     RECT  9.192 21.516 9.264 21.584 ;
     RECT  9.288 21.516 9.36 21.584 ;
     RECT  9.384 21.516 9.456 21.584 ;
     RECT  9.48 21.516 9.552 21.584 ;
     RECT  9.576 21.516 9.648 21.584 ;
     RECT  9.672 21.516 9.744 21.584 ;
     RECT  9.768 21.516 9.84 21.584 ;
     RECT  9.864 21.516 9.936 21.584 ;
     RECT  9.96 21.516 10.032 21.584 ;
     RECT  10.056 21.516 10.128 21.584 ;
     RECT  10.152 21.516 10.224 21.584 ;
     RECT  10.248 21.516 10.32 21.584 ;
     RECT  10.344 21.516 10.416 21.584 ;
     RECT  10.44 21.516 10.512 21.584 ;
     RECT  10.536 21.516 10.608 21.584 ;
     RECT  10.632 21.516 10.704 21.584 ;
     RECT  10.728 21.516 10.8 21.584 ;
     RECT  10.824 21.516 10.896 21.584 ;
     RECT  10.92 21.516 10.992 21.584 ;
     RECT  11.016 21.516 11.088 21.584 ;
     RECT  11.112 21.516 11.184 21.584 ;
     RECT  11.208 21.516 11.28 21.584 ;
     RECT  11.304 21.516 11.376 21.584 ;
     RECT  11.4 21.516 11.472 21.584 ;
     RECT  11.496 21.516 11.568 21.584 ;
     RECT  11.592 0.084 12.912 0.18 ;
     RECT  11.496 0.18 13.008 1.763 ;
     RECT  9.888 13.859 10.368 14.485 ;
     RECT  10.812 14.387 11.544 14.773 ;
     RECT  8.856 14.485 10.368 14.963 ;
     RECT  10.812 14.773 11.952 16.307 ;
     RECT  11.976 14.773 13.2 16.307 ;
     RECT  13.656 16.019 14.976 16.115 ;
     RECT  10.812 16.307 13.2 17.029 ;
     RECT  8.112 16.403 8.856 17.461 ;
     RECT  11.88 17.029 13.2 19.463 ;
     RECT  6.264 17.077 7.392 17.123 ;
     RECT  9.384 17.461 10.5 17.509 ;
     RECT  9.48 17.509 10.5 17.989 ;
  END
END hbfd_rly_48_NS_rr
END LIBRARY
